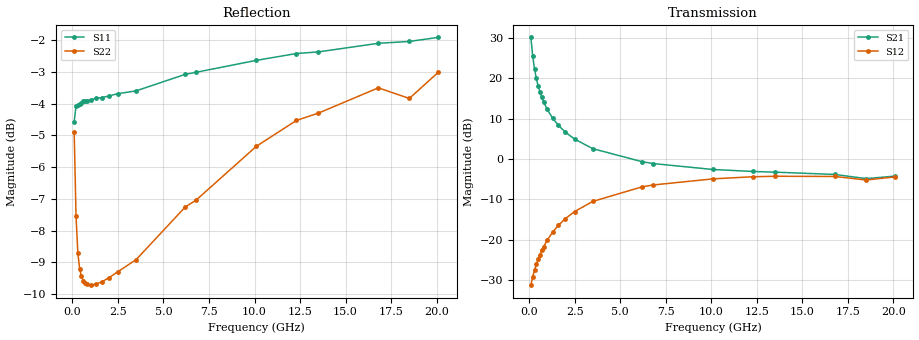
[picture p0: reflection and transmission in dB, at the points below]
!  Infineon Technologies AG
! BFR380L3 , PF131585-7, No.6, Th 09.10.01, soldered on pcb-board, measured with PP GSG850
!  Vce=0.5 V,  Ic=30.0 mA
! Common Emitter S-Parameters:  15. November 2001
#  GHz  S  MA  R  50
! f  S11  S21  S12  S22
! GHz  Mag  Ang  Mag  Ang  Mag  Ang  Mag  Ang
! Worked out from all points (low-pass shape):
!   201 points, 100 MHz to 20.1 GHz, reference 50 ohm
!   highest |S21| = 30.13 dB at 100 MHz (marker M1); lowest = -4.9 dB at 18.5 GHz (marker M2)
!   |S21| within 3 dB of the highest: start of sweep to 164.7 MHz
!   lowest |S11| = -4.6 dB at 100 MHz (marker M3), VSWR 3.89, Z = 17.2 - j27.9 ohm
!   |S11| at or under -10 dB: nowhere
!   |S22| runs from -9.7 to -3.0 dB; largest |S21 - S12| = 32
!   S11 on the Smith chart (normalised r, x): 100 MHz: 0.34, -0.56; 400 MHz: 0.23, -0.11; 2.5 GHz: 0.23, +0.28; 6.2 GHz: 0.28, +0.75; 12.3 GHz: 0.47, +1.50; 20.1 GHz: 0.94, +2.60
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0.1  0.5908 -117.1  32.11 123.9  0.02727 52.3  0.5684 -81.4
0.2  0.6254 -147.3  18.83 106.5  0.03461 48.7  0.4198 -115.9
0.3  0.6279 -159.8  13.06 99.1  0.04182 52.3  0.3673 -134.0
0.4  0.6304 -167.1  9.956 94.2  0.04932 56.0  0.3466 -145.1
0.5  0.6316 -172.4  8.026 90.6  0.05694 58.7  0.3372 -152.6
0.6  0.6362 -176.3  6.727 87.8  0.06518 60.6  0.3319 -158.0
0.7  0.6361 -179.5  5.796 85.2  0.07329 62.0  0.3295 -162.2
0.8  0.6378 177.8  5.089 82.9  0.0818 62.9  0.3277 -165.6
1  0.6383 173.0  4.105 78.8  0.09858 64.0  0.3268 -170.9
1.3  0.6434 166.9  3.193 73.4  0.1241 64.0  0.3281 -176.7
1.6  0.6444 161.4  2.628 68.3  0.1496 63.1  0.3305 178.9
2  0.6484 155.0  2.142 62.1  0.1826 61.0  0.3356 173.9
2.5  0.6539 147.4  1.763 54.9  0.2225 57.7  0.3431 168.4
3.5  0.6605 133.6  1.34 42.0  0.2975 50.1  0.3584 158.9
6.2  0.7013 103.7  0.9246 15.8  0.4504 29.6  0.4338 135.5
6.8  0.7066 98.2  0.8772 11.1  0.475 25.1  0.4448 130.1
10.1  0.7377 74.6  0.7396 -8.0  0.5662 4.2  0.5403 107.3
12.3  0.7562 64.0  0.6991 -18.1  0.6013 -8.2  0.5934 92.8
13.5  0.7606 58.5  0.6855 -23.5  0.6096 -14.5  0.6092 86.1
16.8  0.7847 46.9  0.642 -34.8  0.6064 -28.6  0.6678 69.3
18.5  0.79 45.0  0.5701 -41.9  0.5476 -36.4  0.6426 65.3
20.1  0.8017 38.0  0.6122 -45.3  0.5988 -41.0  0.7069 55.7
